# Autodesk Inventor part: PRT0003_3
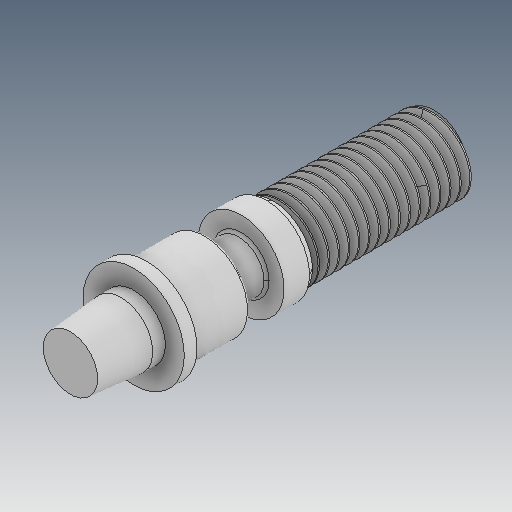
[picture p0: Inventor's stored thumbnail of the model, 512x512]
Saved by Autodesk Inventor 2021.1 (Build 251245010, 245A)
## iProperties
Created: 2019-04
Part Number: PRT0003_3
Material: Ogólny
Document SubType Name: Modeling
Designer: user
Density: 1 g/cm^3
Appearance: Domyślna
Author: user
Revision Number: ÈÎºÎ
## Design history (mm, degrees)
feature "ÊäÈë1"
node "Bryła1"
